VERSION 5.8 ;
BUSBITCHARS "[]" ;
DIVIDERCHAR "/" ;
UNITS
    DATABASE MICRONS 1000 ;
END UNITS

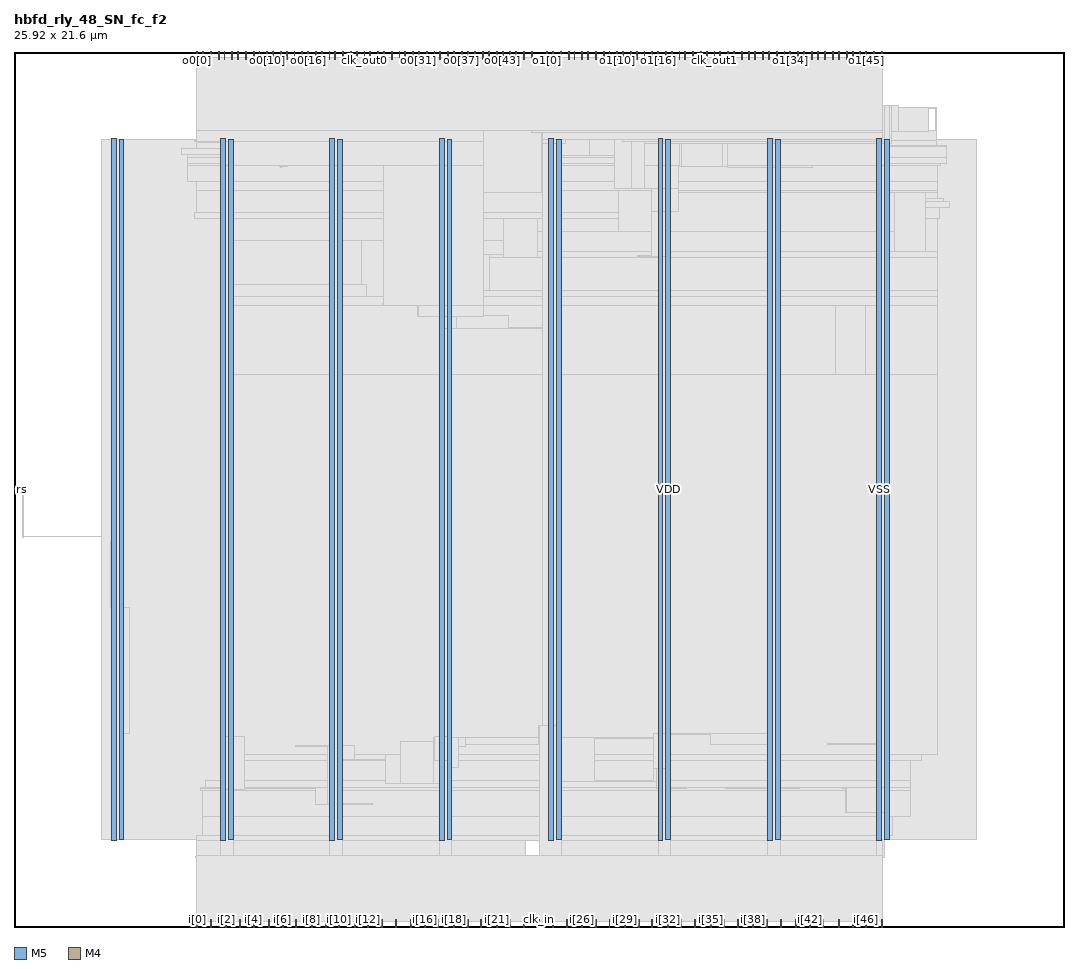
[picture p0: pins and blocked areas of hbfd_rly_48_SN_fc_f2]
MACRO hbfd_rly_48_SN_fc_f2
  FOREIGN hbfd_rly_48_SN_fc_f2 0 0 ;
  CLASS BLOCK ;
  SIZE 25.92 BY 21.6 ;
  PIN clk_in
    DIRECTION INPUT ;
    USE SIGNAL ;
    PORT
      LAYER M5 ;
        RECT  12.96 0 12.984 0.192 ;
    END
  END clk_in
  PIN clk_out0
    DIRECTION OUTPUT ;
    USE SIGNAL ;
    PORT
      LAYER M5 ;
        RECT  8.64 21.408 8.664 21.6 ;
    END
  END clk_out0
  PIN clk_out1
    DIRECTION OUTPUT ;
    USE SIGNAL ;
    PORT
      LAYER M5 ;
        RECT  17.28 21.408 17.304 21.6 ;
    END
  END clk_out1
  PIN i[0]
    DIRECTION INPUT ;
    USE SIGNAL ;
    PORT
      LAYER M5 ;
        RECT  4.512 0 4.536 0.192 ;
    END
  END i[0]
  PIN i[10]
    DIRECTION INPUT ;
    USE SIGNAL ;
    PORT
      LAYER M5 ;
        RECT  8.016 0 8.04 0.192 ;
    END
  END i[10]
  PIN i[11]
    DIRECTION INPUT ;
    USE SIGNAL ;
    PORT
      LAYER M5 ;
        RECT  8.4 0 8.424 0.192 ;
    END
  END i[11]
  PIN i[12]
    DIRECTION INPUT ;
    USE SIGNAL ;
    PORT
      LAYER M5 ;
        RECT  8.736 0 8.76 0.192 ;
    END
  END i[12]
  PIN i[13]
    DIRECTION INPUT ;
    USE SIGNAL ;
    PORT
      LAYER M5 ;
        RECT  9.072 0 9.096 0.192 ;
    END
  END i[13]
  PIN i[14]
    DIRECTION INPUT ;
    USE SIGNAL ;
    PORT
      LAYER M5 ;
        RECT  9.408 0 9.432 0.192 ;
    END
  END i[14]
  PIN i[15]
    DIRECTION INPUT ;
    USE SIGNAL ;
    PORT
      LAYER M5 ;
        RECT  9.792 0 9.816 0.192 ;
    END
  END i[15]
  PIN i[16]
    DIRECTION INPUT ;
    USE SIGNAL ;
    PORT
      LAYER M5 ;
        RECT  10.128 0 10.152 0.192 ;
    END
  END i[16]
  PIN i[17]
    DIRECTION INPUT ;
    USE SIGNAL ;
    PORT
      LAYER M5 ;
        RECT  10.464 0 10.488 0.192 ;
    END
  END i[17]
  PIN i[18]
    DIRECTION INPUT ;
    USE SIGNAL ;
    PORT
      LAYER M5 ;
        RECT  10.848 0 10.872 0.192 ;
    END
  END i[18]
  PIN i[19]
    DIRECTION INPUT ;
    USE SIGNAL ;
    PORT
      LAYER M5 ;
        RECT  11.184 0 11.208 0.192 ;
    END
  END i[19]
  PIN i[1]
    DIRECTION INPUT ;
    USE SIGNAL ;
    PORT
      LAYER M5 ;
        RECT  4.848 0 4.872 0.192 ;
    END
  END i[1]
  PIN i[20]
    DIRECTION INPUT ;
    USE SIGNAL ;
    PORT
      LAYER M5 ;
        RECT  11.52 0 11.544 0.192 ;
    END
  END i[20]
  PIN i[21]
    DIRECTION INPUT ;
    USE SIGNAL ;
    PORT
      LAYER M5 ;
        RECT  11.904 0 11.928 0.192 ;
    END
  END i[21]
  PIN i[22]
    DIRECTION INPUT ;
    USE SIGNAL ;
    PORT
      LAYER M5 ;
        RECT  12.24 0 12.264 0.192 ;
    END
  END i[22]
  PIN i[23]
    DIRECTION INPUT ;
    USE SIGNAL ;
    PORT
      LAYER M5 ;
        RECT  12.576 0 12.6 0.192 ;
    END
  END i[23]
  PIN i[24]
    DIRECTION INPUT ;
    USE SIGNAL ;
    PORT
      LAYER M5 ;
        RECT  13.296 0 13.32 0.192 ;
    END
  END i[24]
  PIN i[25]
    DIRECTION INPUT ;
    USE SIGNAL ;
    PORT
      LAYER M5 ;
        RECT  13.632 0 13.656 0.192 ;
    END
  END i[25]
  PIN i[26]
    DIRECTION INPUT ;
    USE SIGNAL ;
    PORT
      LAYER M5 ;
        RECT  14.016 0 14.04 0.192 ;
    END
  END i[26]
  PIN i[27]
    DIRECTION INPUT ;
    USE SIGNAL ;
    PORT
      LAYER M5 ;
        RECT  14.352 0 14.376 0.192 ;
    END
  END i[27]
  PIN i[28]
    DIRECTION INPUT ;
    USE SIGNAL ;
    PORT
      LAYER M5 ;
        RECT  14.688 0 14.712 0.192 ;
    END
  END i[28]
  PIN i[29]
    DIRECTION INPUT ;
    USE SIGNAL ;
    PORT
      LAYER M5 ;
        RECT  15.072 0 15.096 0.192 ;
    END
  END i[29]
  PIN i[2]
    DIRECTION INPUT ;
    USE SIGNAL ;
    PORT
      LAYER M5 ;
        RECT  5.232 0 5.256 0.192 ;
    END
  END i[2]
  PIN i[30]
    DIRECTION INPUT ;
    USE SIGNAL ;
    PORT
      LAYER M5 ;
        RECT  15.408 0 15.432 0.192 ;
    END
  END i[30]
  PIN i[31]
    DIRECTION INPUT ;
    USE SIGNAL ;
    PORT
      LAYER M5 ;
        RECT  15.744 0 15.768 0.192 ;
    END
  END i[31]
  PIN i[32]
    DIRECTION INPUT ;
    USE SIGNAL ;
    PORT
      LAYER M5 ;
        RECT  16.128 0 16.152 0.192 ;
    END
  END i[32]
  PIN i[33]
    DIRECTION INPUT ;
    USE SIGNAL ;
    PORT
      LAYER M5 ;
        RECT  16.464 0 16.488 0.192 ;
    END
  END i[33]
  PIN i[34]
    DIRECTION INPUT ;
    USE SIGNAL ;
    PORT
      LAYER M5 ;
        RECT  16.8 0 16.824 0.192 ;
    END
  END i[34]
  PIN i[35]
    DIRECTION INPUT ;
    USE SIGNAL ;
    PORT
      LAYER M5 ;
        RECT  17.184 0 17.208 0.192 ;
    END
  END i[35]
  PIN i[36]
    DIRECTION INPUT ;
    USE SIGNAL ;
    PORT
      LAYER M5 ;
        RECT  17.52 0 17.544 0.192 ;
    END
  END i[36]
  PIN i[37]
    DIRECTION INPUT ;
    USE SIGNAL ;
    PORT
      LAYER M5 ;
        RECT  17.856 0 17.88 0.192 ;
    END
  END i[37]
  PIN i[38]
    DIRECTION INPUT ;
    USE SIGNAL ;
    PORT
      LAYER M5 ;
        RECT  18.24 0 18.264 0.192 ;
    END
  END i[38]
  PIN i[39]
    DIRECTION INPUT ;
    USE SIGNAL ;
    PORT
      LAYER M5 ;
        RECT  18.576 0 18.6 0.192 ;
    END
  END i[39]
  PIN i[3]
    DIRECTION INPUT ;
    USE SIGNAL ;
    PORT
      LAYER M5 ;
        RECT  5.568 0 5.592 0.192 ;
    END
  END i[3]
  PIN i[40]
    DIRECTION INPUT ;
    USE SIGNAL ;
    PORT
      LAYER M5 ;
        RECT  18.912 0 18.936 0.192 ;
    END
  END i[40]
  PIN i[41]
    DIRECTION INPUT ;
    USE SIGNAL ;
    PORT
      LAYER M5 ;
        RECT  19.296 0 19.32 0.192 ;
    END
  END i[41]
  PIN i[42]
    DIRECTION INPUT ;
    USE SIGNAL ;
    PORT
      LAYER M5 ;
        RECT  19.632 0 19.656 0.192 ;
    END
  END i[42]
  PIN i[43]
    DIRECTION INPUT ;
    USE SIGNAL ;
    PORT
      LAYER M5 ;
        RECT  19.968 0 19.992 0.192 ;
    END
  END i[43]
  PIN i[44]
    DIRECTION INPUT ;
    USE SIGNAL ;
    PORT
      LAYER M5 ;
        RECT  20.352 0 20.376 0.192 ;
    END
  END i[44]
  PIN i[45]
    DIRECTION INPUT ;
    USE SIGNAL ;
    PORT
      LAYER M5 ;
        RECT  20.688 0 20.712 0.192 ;
    END
  END i[45]
  PIN i[46]
    DIRECTION INPUT ;
    USE SIGNAL ;
    PORT
      LAYER M5 ;
        RECT  21.024 0 21.048 0.192 ;
    END
  END i[46]
  PIN i[47]
    DIRECTION INPUT ;
    USE SIGNAL ;
    PORT
      LAYER M5 ;
        RECT  21.408 0 21.432 0.192 ;
    END
  END i[47]
  PIN i[4]
    DIRECTION INPUT ;
    USE SIGNAL ;
    PORT
      LAYER M5 ;
        RECT  5.904 0 5.928 0.192 ;
    END
  END i[4]
  PIN i[5]
    DIRECTION INPUT ;
    USE SIGNAL ;
    PORT
      LAYER M5 ;
        RECT  6.288 0 6.312 0.192 ;
    END
  END i[5]
  PIN i[6]
    DIRECTION INPUT ;
    USE SIGNAL ;
    PORT
      LAYER M5 ;
        RECT  6.624 0 6.648 0.192 ;
    END
  END i[6]
  PIN i[7]
    DIRECTION INPUT ;
    USE SIGNAL ;
    PORT
      LAYER M5 ;
        RECT  6.96 0 6.984 0.192 ;
    END
  END i[7]
  PIN i[8]
    DIRECTION INPUT ;
    USE SIGNAL ;
    PORT
      LAYER M5 ;
        RECT  7.344 0 7.368 0.192 ;
    END
  END i[8]
  PIN i[9]
    DIRECTION INPUT ;
    USE SIGNAL ;
    PORT
      LAYER M5 ;
        RECT  7.68 0 7.704 0.192 ;
    END
  END i[9]
  PIN o0[0]
    DIRECTION OUTPUT ;
    USE SIGNAL ;
    PORT
      LAYER M5 ;
        RECT  4.512 21.408 4.536 21.6 ;
    END
  END o0[0]
  PIN o0[10]
    DIRECTION OUTPUT ;
    USE SIGNAL ;
    PORT
      LAYER M5 ;
        RECT  6.24 21.408 6.264 21.6 ;
    END
  END o0[10]
  PIN o0[11]
    DIRECTION OUTPUT ;
    USE SIGNAL ;
    PORT
      LAYER M5 ;
        RECT  6.384 21.408 6.408 21.6 ;
    END
  END o0[11]
  PIN o0[12]
    DIRECTION OUTPUT ;
    USE SIGNAL ;
    PORT
      LAYER M5 ;
        RECT  6.576 21.408 6.6 21.6 ;
    END
  END o0[12]
  PIN o0[13]
    DIRECTION OUTPUT ;
    USE SIGNAL ;
    PORT
      LAYER M5 ;
        RECT  6.72 21.408 6.744 21.6 ;
    END
  END o0[13]
  PIN o0[14]
    DIRECTION OUTPUT ;
    USE SIGNAL ;
    PORT
      LAYER M5 ;
        RECT  6.912 21.408 6.936 21.6 ;
    END
  END o0[14]
  PIN o0[15]
    DIRECTION OUTPUT ;
    USE SIGNAL ;
    PORT
      LAYER M5 ;
        RECT  7.104 21.408 7.128 21.6 ;
    END
  END o0[15]
  PIN o0[16]
    DIRECTION OUTPUT ;
    USE SIGNAL ;
    PORT
      LAYER M5 ;
        RECT  7.248 21.408 7.272 21.6 ;
    END
  END o0[16]
  PIN o0[17]
    DIRECTION OUTPUT ;
    USE SIGNAL ;
    PORT
      LAYER M5 ;
        RECT  7.44 21.408 7.464 21.6 ;
    END
  END o0[17]
  PIN o0[18]
    DIRECTION OUTPUT ;
    USE SIGNAL ;
    PORT
      LAYER M5 ;
        RECT  7.584 21.408 7.608 21.6 ;
    END
  END o0[18]
  PIN o0[19]
    DIRECTION OUTPUT ;
    USE SIGNAL ;
    PORT
      LAYER M5 ;
        RECT  7.776 21.408 7.8 21.6 ;
    END
  END o0[19]
  PIN o0[1]
    DIRECTION OUTPUT ;
    USE SIGNAL ;
    PORT
      LAYER M5 ;
        RECT  4.656 21.408 4.68 21.6 ;
    END
  END o0[1]
  PIN o0[20]
    DIRECTION OUTPUT ;
    USE SIGNAL ;
    PORT
      LAYER M5 ;
        RECT  7.92 21.408 7.944 21.6 ;
    END
  END o0[20]
  PIN o0[21]
    DIRECTION OUTPUT ;
    USE SIGNAL ;
    PORT
      LAYER M5 ;
        RECT  8.112 21.408 8.136 21.6 ;
    END
  END o0[21]
  PIN o0[22]
    DIRECTION OUTPUT ;
    USE SIGNAL ;
    PORT
      LAYER M5 ;
        RECT  8.304 21.408 8.328 21.6 ;
    END
  END o0[22]
  PIN o0[23]
    DIRECTION OUTPUT ;
    USE SIGNAL ;
    PORT
      LAYER M5 ;
        RECT  8.448 21.408 8.472 21.6 ;
    END
  END o0[23]
  PIN o0[24]
    DIRECTION OUTPUT ;
    USE SIGNAL ;
    PORT
      LAYER M5 ;
        RECT  8.784 21.408 8.808 21.6 ;
    END
  END o0[24]
  PIN o0[25]
    DIRECTION OUTPUT ;
    USE SIGNAL ;
    PORT
      LAYER M5 ;
        RECT  8.976 21.408 9 21.6 ;
    END
  END o0[25]
  PIN o0[26]
    DIRECTION OUTPUT ;
    USE SIGNAL ;
    PORT
      LAYER M5 ;
        RECT  9.12 21.408 9.144 21.6 ;
    END
  END o0[26]
  PIN o0[27]
    DIRECTION OUTPUT ;
    USE SIGNAL ;
    PORT
      LAYER M5 ;
        RECT  9.312 21.408 9.336 21.6 ;
    END
  END o0[27]
  PIN o0[28]
    DIRECTION OUTPUT ;
    USE SIGNAL ;
    PORT
      LAYER M5 ;
        RECT  9.504 21.408 9.528 21.6 ;
    END
  END o0[28]
  PIN o0[29]
    DIRECTION OUTPUT ;
    USE SIGNAL ;
    PORT
      LAYER M5 ;
        RECT  9.648 21.408 9.672 21.6 ;
    END
  END o0[29]
  PIN o0[2]
    DIRECTION OUTPUT ;
    USE SIGNAL ;
    PORT
      LAYER M5 ;
        RECT  4.848 21.408 4.872 21.6 ;
    END
  END o0[2]
  PIN o0[30]
    DIRECTION OUTPUT ;
    USE SIGNAL ;
    PORT
      LAYER M5 ;
        RECT  9.84 21.408 9.864 21.6 ;
    END
  END o0[30]
  PIN o0[31]
    DIRECTION OUTPUT ;
    USE SIGNAL ;
    PORT
      LAYER M5 ;
        RECT  9.984 21.408 10.008 21.6 ;
    END
  END o0[31]
  PIN o0[32]
    DIRECTION OUTPUT ;
    USE SIGNAL ;
    PORT
      LAYER M5 ;
        RECT  10.176 21.408 10.2 21.6 ;
    END
  END o0[32]
  PIN o0[33]
    DIRECTION OUTPUT ;
    USE SIGNAL ;
    PORT
      LAYER M5 ;
        RECT  10.368 21.408 10.392 21.6 ;
    END
  END o0[33]
  PIN o0[34]
    DIRECTION OUTPUT ;
    USE SIGNAL ;
    PORT
      LAYER M5 ;
        RECT  10.512 21.408 10.536 21.6 ;
    END
  END o0[34]
  PIN o0[35]
    DIRECTION OUTPUT ;
    USE SIGNAL ;
    PORT
      LAYER M5 ;
        RECT  10.704 21.408 10.728 21.6 ;
    END
  END o0[35]
  PIN o0[36]
    DIRECTION OUTPUT ;
    USE SIGNAL ;
    PORT
      LAYER M5 ;
        RECT  10.848 21.408 10.872 21.6 ;
    END
  END o0[36]
  PIN o0[37]
    DIRECTION OUTPUT ;
    USE SIGNAL ;
    PORT
      LAYER M5 ;
        RECT  11.04 21.408 11.064 21.6 ;
    END
  END o0[37]
  PIN o0[38]
    DIRECTION OUTPUT ;
    USE SIGNAL ;
    PORT
      LAYER M5 ;
        RECT  11.184 21.408 11.208 21.6 ;
    END
  END o0[38]
  PIN o0[39]
    DIRECTION OUTPUT ;
    USE SIGNAL ;
    PORT
      LAYER M5 ;
        RECT  11.376 21.408 11.4 21.6 ;
    END
  END o0[39]
  PIN o0[3]
    DIRECTION OUTPUT ;
    USE SIGNAL ;
    PORT
      LAYER M5 ;
        RECT  5.04 21.408 5.064 21.6 ;
    END
  END o0[3]
  PIN o0[40]
    DIRECTION OUTPUT ;
    USE SIGNAL ;
    PORT
      LAYER M5 ;
        RECT  11.568 21.408 11.592 21.6 ;
    END
  END o0[40]
  PIN o0[41]
    DIRECTION OUTPUT ;
    USE SIGNAL ;
    PORT
      LAYER M5 ;
        RECT  11.712 21.408 11.736 21.6 ;
    END
  END o0[41]
  PIN o0[42]
    DIRECTION OUTPUT ;
    USE SIGNAL ;
    PORT
      LAYER M5 ;
        RECT  11.904 21.408 11.928 21.6 ;
    END
  END o0[42]
  PIN o0[43]
    DIRECTION OUTPUT ;
    USE SIGNAL ;
    PORT
      LAYER M5 ;
        RECT  12.048 21.408 12.072 21.6 ;
    END
  END o0[43]
  PIN o0[44]
    DIRECTION OUTPUT ;
    USE SIGNAL ;
    PORT
      LAYER M5 ;
        RECT  12.24 21.408 12.264 21.6 ;
    END
  END o0[44]
  PIN o0[45]
    DIRECTION OUTPUT ;
    USE SIGNAL ;
    PORT
      LAYER M5 ;
        RECT  12.384 21.408 12.408 21.6 ;
    END
  END o0[45]
  PIN o0[46]
    DIRECTION OUTPUT ;
    USE SIGNAL ;
    PORT
      LAYER M5 ;
        RECT  12.576 21.408 12.6 21.6 ;
    END
  END o0[46]
  PIN o0[47]
    DIRECTION OUTPUT ;
    USE SIGNAL ;
    PORT
      LAYER M5 ;
        RECT  12.768 21.408 12.792 21.6 ;
    END
  END o0[47]
  PIN o0[4]
    DIRECTION OUTPUT ;
    USE SIGNAL ;
    PORT
      LAYER M5 ;
        RECT  5.184 21.408 5.208 21.6 ;
    END
  END o0[4]
  PIN o0[5]
    DIRECTION OUTPUT ;
    USE SIGNAL ;
    PORT
      LAYER M5 ;
        RECT  5.376 21.408 5.4 21.6 ;
    END
  END o0[5]
  PIN o0[6]
    DIRECTION OUTPUT ;
    USE SIGNAL ;
    PORT
      LAYER M5 ;
        RECT  5.52 21.408 5.544 21.6 ;
    END
  END o0[6]
  PIN o0[7]
    DIRECTION OUTPUT ;
    USE SIGNAL ;
    PORT
      LAYER M5 ;
        RECT  5.712 21.408 5.736 21.6 ;
    END
  END o0[7]
  PIN o0[8]
    DIRECTION OUTPUT ;
    USE SIGNAL ;
    PORT
      LAYER M5 ;
        RECT  5.904 21.408 5.928 21.6 ;
    END
  END o0[8]
  PIN o0[9]
    DIRECTION OUTPUT ;
    USE SIGNAL ;
    PORT
      LAYER M5 ;
        RECT  6.048 21.408 6.072 21.6 ;
    END
  END o0[9]
  PIN o1[0]
    DIRECTION OUTPUT ;
    USE SIGNAL ;
    PORT
      LAYER M5 ;
        RECT  13.152 21.408 13.176 21.6 ;
    END
  END o1[0]
  PIN o1[10]
    DIRECTION OUTPUT ;
    USE SIGNAL ;
    PORT
      LAYER M5 ;
        RECT  14.88 21.408 14.904 21.6 ;
    END
  END o1[10]
  PIN o1[11]
    DIRECTION OUTPUT ;
    USE SIGNAL ;
    PORT
      LAYER M5 ;
        RECT  15.024 21.408 15.048 21.6 ;
    END
  END o1[11]
  PIN o1[12]
    DIRECTION OUTPUT ;
    USE SIGNAL ;
    PORT
      LAYER M5 ;
        RECT  15.216 21.408 15.24 21.6 ;
    END
  END o1[12]
  PIN o1[13]
    DIRECTION OUTPUT ;
    USE SIGNAL ;
    PORT
      LAYER M5 ;
        RECT  15.36 21.408 15.384 21.6 ;
    END
  END o1[13]
  PIN o1[14]
    DIRECTION OUTPUT ;
    USE SIGNAL ;
    PORT
      LAYER M5 ;
        RECT  15.552 21.408 15.576 21.6 ;
    END
  END o1[14]
  PIN o1[15]
    DIRECTION OUTPUT ;
    USE SIGNAL ;
    PORT
      LAYER M5 ;
        RECT  15.744 21.408 15.768 21.6 ;
    END
  END o1[15]
  PIN o1[16]
    DIRECTION OUTPUT ;
    USE SIGNAL ;
    PORT
      LAYER M5 ;
        RECT  15.888 21.408 15.912 21.6 ;
    END
  END o1[16]
  PIN o1[17]
    DIRECTION OUTPUT ;
    USE SIGNAL ;
    PORT
      LAYER M5 ;
        RECT  16.08 21.408 16.104 21.6 ;
    END
  END o1[17]
  PIN o1[18]
    DIRECTION OUTPUT ;
    USE SIGNAL ;
    PORT
      LAYER M5 ;
        RECT  16.224 21.408 16.248 21.6 ;
    END
  END o1[18]
  PIN o1[19]
    DIRECTION OUTPUT ;
    USE SIGNAL ;
    PORT
      LAYER M5 ;
        RECT  16.416 21.408 16.44 21.6 ;
    END
  END o1[19]
  PIN o1[1]
    DIRECTION OUTPUT ;
    USE SIGNAL ;
    PORT
      LAYER M5 ;
        RECT  13.296 21.408 13.32 21.6 ;
    END
  END o1[1]
  PIN o1[20]
    DIRECTION OUTPUT ;
    USE SIGNAL ;
    PORT
      LAYER M5 ;
        RECT  16.56 21.408 16.584 21.6 ;
    END
  END o1[20]
  PIN o1[21]
    DIRECTION OUTPUT ;
    USE SIGNAL ;
    PORT
      LAYER M5 ;
        RECT  16.752 21.408 16.776 21.6 ;
    END
  END o1[21]
  PIN o1[22]
    DIRECTION OUTPUT ;
    USE SIGNAL ;
    PORT
      LAYER M5 ;
        RECT  16.944 21.408 16.968 21.6 ;
    END
  END o1[22]
  PIN o1[23]
    DIRECTION OUTPUT ;
    USE SIGNAL ;
    PORT
      LAYER M5 ;
        RECT  17.088 21.408 17.112 21.6 ;
    END
  END o1[23]
  PIN o1[24]
    DIRECTION OUTPUT ;
    USE SIGNAL ;
    PORT
      LAYER M5 ;
        RECT  17.424 21.408 17.448 21.6 ;
    END
  END o1[24]
  PIN o1[25]
    DIRECTION OUTPUT ;
    USE SIGNAL ;
    PORT
      LAYER M5 ;
        RECT  17.616 21.408 17.64 21.6 ;
    END
  END o1[25]
  PIN o1[26]
    DIRECTION OUTPUT ;
    USE SIGNAL ;
    PORT
      LAYER M5 ;
        RECT  17.76 21.408 17.784 21.6 ;
    END
  END o1[26]
  PIN o1[27]
    DIRECTION OUTPUT ;
    USE SIGNAL ;
    PORT
      LAYER M5 ;
        RECT  17.952 21.408 17.976 21.6 ;
    END
  END o1[27]
  PIN o1[28]
    DIRECTION OUTPUT ;
    USE SIGNAL ;
    PORT
      LAYER M5 ;
        RECT  18.144 21.408 18.168 21.6 ;
    END
  END o1[28]
  PIN o1[29]
    DIRECTION OUTPUT ;
    USE SIGNAL ;
    PORT
      LAYER M5 ;
        RECT  18.288 21.408 18.312 21.6 ;
    END
  END o1[29]
  PIN o1[2]
    DIRECTION OUTPUT ;
    USE SIGNAL ;
    PORT
      LAYER M5 ;
        RECT  13.488 21.408 13.512 21.6 ;
    END
  END o1[2]
  PIN o1[30]
    DIRECTION OUTPUT ;
    USE SIGNAL ;
    PORT
      LAYER M5 ;
        RECT  18.48 21.408 18.504 21.6 ;
    END
  END o1[30]
  PIN o1[31]
    DIRECTION OUTPUT ;
    USE SIGNAL ;
    PORT
      LAYER M5 ;
        RECT  18.624 21.408 18.648 21.6 ;
    END
  END o1[31]
  PIN o1[32]
    DIRECTION OUTPUT ;
    USE SIGNAL ;
    PORT
      LAYER M5 ;
        RECT  18.816 21.408 18.84 21.6 ;
    END
  END o1[32]
  PIN o1[33]
    DIRECTION OUTPUT ;
    USE SIGNAL ;
    PORT
      LAYER M5 ;
        RECT  19.008 21.408 19.032 21.6 ;
    END
  END o1[33]
  PIN o1[34]
    DIRECTION OUTPUT ;
    USE SIGNAL ;
    PORT
      LAYER M5 ;
        RECT  19.152 21.408 19.176 21.6 ;
    END
  END o1[34]
  PIN o1[35]
    DIRECTION OUTPUT ;
    USE SIGNAL ;
    PORT
      LAYER M5 ;
        RECT  19.344 21.408 19.368 21.6 ;
    END
  END o1[35]
  PIN o1[36]
    DIRECTION OUTPUT ;
    USE SIGNAL ;
    PORT
      LAYER M5 ;
        RECT  19.488 21.408 19.512 21.6 ;
    END
  END o1[36]
  PIN o1[37]
    DIRECTION OUTPUT ;
    USE SIGNAL ;
    PORT
      LAYER M5 ;
        RECT  19.68 21.408 19.704 21.6 ;
    END
  END o1[37]
  PIN o1[38]
    DIRECTION OUTPUT ;
    USE SIGNAL ;
    PORT
      LAYER M5 ;
        RECT  19.824 21.408 19.848 21.6 ;
    END
  END o1[38]
  PIN o1[39]
    DIRECTION OUTPUT ;
    USE SIGNAL ;
    PORT
      LAYER M5 ;
        RECT  20.016 21.408 20.04 21.6 ;
    END
  END o1[39]
  PIN o1[3]
    DIRECTION OUTPUT ;
    USE SIGNAL ;
    PORT
      LAYER M5 ;
        RECT  13.68 21.408 13.704 21.6 ;
    END
  END o1[3]
  PIN o1[40]
    DIRECTION OUTPUT ;
    USE SIGNAL ;
    PORT
      LAYER M5 ;
        RECT  20.208 21.408 20.232 21.6 ;
    END
  END o1[40]
  PIN o1[41]
    DIRECTION OUTPUT ;
    USE SIGNAL ;
    PORT
      LAYER M5 ;
        RECT  20.352 21.408 20.376 21.6 ;
    END
  END o1[41]
  PIN o1[42]
    DIRECTION OUTPUT ;
    USE SIGNAL ;
    PORT
      LAYER M5 ;
        RECT  20.544 21.408 20.568 21.6 ;
    END
  END o1[42]
  PIN o1[43]
    DIRECTION OUTPUT ;
    USE SIGNAL ;
    PORT
      LAYER M5 ;
        RECT  20.688 21.408 20.712 21.6 ;
    END
  END o1[43]
  PIN o1[44]
    DIRECTION OUTPUT ;
    USE SIGNAL ;
    PORT
      LAYER M5 ;
        RECT  20.88 21.408 20.904 21.6 ;
    END
  END o1[44]
  PIN o1[45]
    DIRECTION OUTPUT ;
    USE SIGNAL ;
    PORT
      LAYER M5 ;
        RECT  21.024 21.408 21.048 21.6 ;
    END
  END o1[45]
  PIN o1[46]
    DIRECTION OUTPUT ;
    USE SIGNAL ;
    PORT
      LAYER M5 ;
        RECT  21.216 21.408 21.24 21.6 ;
    END
  END o1[46]
  PIN o1[47]
    DIRECTION OUTPUT ;
    USE SIGNAL ;
    PORT
      LAYER M5 ;
        RECT  21.408 21.408 21.432 21.6 ;
    END
  END o1[47]
  PIN o1[4]
    DIRECTION OUTPUT ;
    USE SIGNAL ;
    PORT
      LAYER M5 ;
        RECT  13.824 21.408 13.848 21.6 ;
    END
  END o1[4]
  PIN o1[5]
    DIRECTION OUTPUT ;
    USE SIGNAL ;
    PORT
      LAYER M5 ;
        RECT  14.016 21.408 14.04 21.6 ;
    END
  END o1[5]
  PIN o1[6]
    DIRECTION OUTPUT ;
    USE SIGNAL ;
    PORT
      LAYER M5 ;
        RECT  14.16 21.408 14.184 21.6 ;
    END
  END o1[6]
  PIN o1[7]
    DIRECTION OUTPUT ;
    USE SIGNAL ;
    PORT
      LAYER M5 ;
        RECT  14.352 21.408 14.376 21.6 ;
    END
  END o1[7]
  PIN o1[8]
    DIRECTION OUTPUT ;
    USE SIGNAL ;
    PORT
      LAYER M5 ;
        RECT  14.544 21.408 14.568 21.6 ;
    END
  END o1[8]
  PIN o1[9]
    DIRECTION OUTPUT ;
    USE SIGNAL ;
    PORT
      LAYER M5 ;
        RECT  14.688 21.408 14.712 21.6 ;
    END
  END o1[9]
  PIN rs
    DIRECTION INPUT ;
    USE SIGNAL ;
    PORT
      LAYER M4 ;
        RECT  0 10.8 0.192 10.824 ;
    END
  END rs
  PIN VDD
    DIRECTION INOUT ;
    USE POWER ;
    PORT
      LAYER M5 ;
        RECT  21.492 2.151 21.612 19.449 ;
        RECT  18.792 2.151 18.912 19.449 ;
        RECT  16.092 2.151 16.212 19.449 ;
        RECT  13.392 2.151 13.512 19.449 ;
        RECT  10.692 2.151 10.812 19.449 ;
        RECT  7.992 2.151 8.112 19.449 ;
        RECT  5.292 2.151 5.412 19.449 ;
        RECT  2.592 2.151 2.712 19.449 ;
    END
  END VDD
  PIN VSS
    DIRECTION INOUT ;
    USE GROUND ;
    PORT
      LAYER M5 ;
        RECT  21.3 2.137 21.42 19.463 ;
        RECT  18.6 2.137 18.72 19.463 ;
        RECT  15.9 2.137 16.02 19.463 ;
        RECT  13.2 2.137 13.32 19.463 ;
        RECT  10.5 2.137 10.62 19.463 ;
        RECT  7.8 2.137 7.92 19.463 ;
        RECT  5.1 2.137 5.22 19.463 ;
        RECT  2.4 2.137 2.52 19.463 ;
    END
  END VSS
  OBS
    LAYER RVTN ;
     RECT  2.16 2.16 23.76 2.295 ;
     RECT  2.16 2.565 23.76 2.835 ;
     RECT  2.16 3.105 23.76 3.375 ;
     RECT  2.16 3.645 23.76 3.915 ;
     RECT  2.16 4.185 23.76 4.455 ;
     RECT  2.16 4.725 23.76 4.995 ;
     RECT  2.16 5.265 23.76 5.535 ;
     RECT  2.16 5.805 23.76 6.075 ;
     RECT  2.16 6.345 23.76 6.615 ;
     RECT  2.16 6.885 23.76 7.155 ;
     RECT  2.16 7.425 23.76 7.695 ;
     RECT  2.16 7.965 23.76 8.235 ;
     RECT  2.16 8.505 23.76 8.775 ;
     RECT  2.16 9.045 23.76 9.315 ;
     RECT  2.16 9.585 23.76 9.855 ;
     RECT  2.16 10.125 23.76 10.395 ;
     RECT  2.16 10.665 23.76 10.935 ;
     RECT  2.16 11.205 23.76 11.475 ;
     RECT  2.16 11.745 23.76 12.015 ;
     RECT  2.16 12.285 23.76 12.555 ;
     RECT  2.16 12.825 23.76 13.095 ;
     RECT  2.16 13.365 23.76 13.635 ;
     RECT  2.16 13.905 23.76 14.175 ;
     RECT  2.16 14.445 23.76 14.715 ;
     RECT  2.16 14.985 23.76 15.255 ;
     RECT  2.16 15.525 23.76 15.795 ;
     RECT  2.16 16.065 23.76 16.335 ;
     RECT  2.16 16.605 23.76 16.875 ;
     RECT  2.16 17.145 23.76 17.415 ;
     RECT  2.16 17.685 23.76 17.955 ;
     RECT  2.16 18.225 23.76 18.495 ;
     RECT  2.16 18.765 23.76 19.035 ;
     RECT  2.16 19.305 23.76 19.44 ;
    LAYER RVTP ;
     RECT  2.16 2.295 23.76 2.565 ;
     RECT  2.16 2.835 23.76 3.105 ;
     RECT  2.16 3.375 23.76 3.645 ;
     RECT  2.16 3.915 23.76 4.185 ;
     RECT  2.16 4.455 23.76 4.725 ;
     RECT  2.16 4.995 23.76 5.265 ;
     RECT  2.16 5.535 23.76 5.805 ;
     RECT  2.16 6.075 23.76 6.345 ;
     RECT  2.16 6.615 23.76 6.885 ;
     RECT  2.16 7.155 23.76 7.425 ;
     RECT  2.16 7.695 23.76 7.965 ;
     RECT  2.16 8.235 23.76 8.505 ;
     RECT  2.16 8.775 23.76 9.045 ;
     RECT  2.16 9.315 23.76 9.585 ;
     RECT  2.16 9.855 23.76 10.125 ;
     RECT  2.16 10.395 23.76 10.665 ;
     RECT  2.16 10.935 23.76 11.205 ;
     RECT  2.16 11.475 23.76 11.745 ;
     RECT  2.16 12.015 23.76 12.285 ;
     RECT  2.16 12.555 23.76 12.825 ;
     RECT  2.16 13.095 23.76 13.365 ;
     RECT  2.16 13.635 23.76 13.905 ;
     RECT  2.16 14.175 23.76 14.445 ;
     RECT  2.16 14.715 23.76 14.985 ;
     RECT  2.16 15.255 23.76 15.525 ;
     RECT  2.16 15.795 23.76 16.065 ;
     RECT  2.16 16.335 23.76 16.605 ;
     RECT  2.16 16.875 23.76 17.145 ;
     RECT  2.16 17.415 23.76 17.685 ;
     RECT  2.16 17.955 23.76 18.225 ;
     RECT  2.16 18.495 23.76 18.765 ;
     RECT  2.16 19.035 23.76 19.305 ;
    LAYER M1 ;
     RECT  2.16 2.151 23.76 19.449 ;
    LAYER M2 ;
     RECT  0.211 9.63 2.16 9.648 ;
     RECT  2.16 2.151 23.76 19.449 ;
    LAYER M3 ;
     RECT  4.5 1.723 12.618 2.143 ;
     RECT  13.356 1.723 21.474 2.143 ;
     RECT  4.5 2.143 21.474 2.255 ;
     RECT  4.644 2.255 21.474 2.263 ;
     RECT  2.415 2.143 2.505 2.413 ;
     RECT  4.644 2.263 21.69 2.731 ;
     RECT  4.644 2.731 22.122 3.379 ;
     RECT  4.608 3.379 22.122 3.437 ;
     RECT  4.716 3.437 22.122 3.605 ;
     RECT  5.115 3.605 22.122 4.117 ;
     RECT  5.115 4.117 22.41 4.261 ;
     RECT  2.415 2.413 2.697 4.765 ;
     RECT  2.415 4.765 2.862 7.889 ;
     RECT  2.415 7.889 2.697 7.897 ;
     RECT  2.376 7.897 2.697 9.509 ;
     RECT  0.216 9.625 0.234 10.829 ;
     RECT  5.115 4.261 22.806 13.631 ;
     RECT  5.115 13.631 20.286 15.331 ;
     RECT  21.024 13.631 22.806 15.331 ;
     RECT  5.115 15.331 22.806 15.557 ;
     RECT  9.468 15.557 22.806 15.719 ;
     RECT  5.115 15.557 8.694 15.863 ;
     RECT  9.576 15.719 10.854 16.501 ;
     RECT  11.736 15.719 22.806 16.529 ;
     RECT  9.396 16.501 10.854 16.609 ;
     RECT  11.736 16.529 12.078 16.609 ;
     RECT  12.924 16.529 22.806 16.673 ;
     RECT  5.115 15.863 8.586 16.951 ;
     RECT  9.396 16.609 12.078 16.951 ;
     RECT  12.924 16.673 21.726 17.177 ;
     RECT  5.115 16.951 12.078 17.491 ;
     RECT  12.924 17.177 14.922 17.491 ;
     RECT  22.5 16.673 22.806 17.491 ;
     RECT  4.464 17.491 14.922 17.645 ;
     RECT  22.5 17.491 22.842 17.761 ;
     RECT  22.5 17.761 23.094 17.915 ;
     RECT  22.5 17.915 22.95 17.987 ;
     RECT  15.876 17.177 21.726 18.121 ;
     RECT  22.5 17.987 22.806 18.121 ;
     RECT  4.5 17.645 14.922 18.193 ;
     RECT  15.876 18.121 22.806 18.193 ;
     RECT  4.5 18.193 22.806 18.391 ;
     RECT  4.284 18.391 22.806 18.805 ;
     RECT  4.284 18.805 22.878 18.841 ;
     RECT  4.284 18.841 23.022 18.995 ;
     RECT  4.284 18.995 8.658 19.075 ;
     RECT  2.415 9.509 2.697 19.187 ;
     RECT  4.14 19.075 8.658 19.229 ;
     RECT  9.54 18.995 23.022 19.265 ;
     RECT  9.54 19.265 14.85 19.277 ;
     RECT  15.66 19.265 23.022 19.301 ;
     RECT  4.5 19.229 8.658 19.373 ;
     RECT  9.576 19.277 14.85 19.373 ;
     RECT  4.5 19.373 6.102 19.421 ;
     RECT  15.66 19.301 22.77 19.421 ;
     RECT  2.415 19.187 2.505 19.457 ;
     RECT  9.9 19.373 14.85 19.469 ;
     RECT  7.164 19.373 8.55 19.613 ;
     RECT  9.9 19.469 14.67 19.613 ;
     RECT  19.98 19.421 22.77 19.661 ;
     RECT  19.98 19.661 21.834 19.709 ;
     RECT  11.88 19.613 14.67 19.757 ;
     RECT  4.608 19.421 6.102 19.997 ;
     RECT  7.164 19.613 7.758 19.997 ;
     RECT  8.532 19.613 8.55 19.997 ;
     RECT  9.9 19.613 11.142 19.997 ;
     RECT  11.88 19.757 11.898 19.997 ;
     RECT  15.66 19.421 19.026 19.997 ;
     RECT  20.016 19.709 21.834 19.997 ;
     RECT  11.088 19.997 11.142 20.045 ;
     RECT  13.032 19.757 14.67 20.045 ;
     RECT  16.056 19.997 18.99 20.093 ;
     RECT  22.752 19.661 22.77 20.237 ;
     RECT  21.816 19.997 21.834 20.285 ;
     RECT  20.232 19.997 20.646 20.381 ;
     RECT  4.788 19.997 5.706 20.573 ;
     RECT  7.2 19.997 7.758 20.573 ;
     RECT  9.9 19.997 9.918 20.573 ;
     RECT  11.124 20.045 11.142 20.573 ;
     RECT  14.652 20.045 14.67 20.573 ;
     RECT  16.056 20.093 18.774 20.573 ;
     RECT  20.628 20.381 20.646 20.573 ;
     RECT  16.488 20.573 18.054 20.621 ;
     RECT  13.032 20.045 13.554 20.669 ;
     RECT  17.496 20.621 17.766 20.669 ;
     RECT  13.536 20.669 13.554 20.717 ;
     RECT  17.748 20.669 17.766 20.717 ;
    LAYER M4 ;
     RECT  0.156 10.8 0.245 10.824 ;
     RECT  2.408 2.148 2.512 19.452 ;
     RECT  2.512 2.418 2.704 19.182 ;
     RECT  4.46 19.392 4.597 19.416 ;
     RECT  4.597 19.392 4.777 19.992 ;
     RECT  4.489 1.728 5.108 1.752 ;
     RECT  4.597 3.408 5.108 3.432 ;
     RECT  4.777 19.392 5.108 20.568 ;
     RECT  5.108 1.728 5.404 20.568 ;
     RECT  5.404 4.656 5.699 4.68 ;
     RECT  5.404 19.968 5.717 20.568 ;
     RECT  5.717 19.968 6.124 19.992 ;
     RECT  5.404 18.816 6.565 18.84 ;
     RECT  6.565 18.768 6.709 18.84 ;
     RECT  6.709 18.768 6.761 19.368 ;
     RECT  6.761 18.816 7.093 19.368 ;
     RECT  6.901 20.544 7.093 20.568 ;
     RECT  5.404 3.408 7.441 3.432 ;
     RECT  7.441 3.024 7.729 3.432 ;
     RECT  6.937 4.464 7.729 4.488 ;
     RECT  7.093 18.816 7.769 20.568 ;
     RECT  5.404 1.728 7.808 1.752 ;
     RECT  7.729 3.024 7.808 4.488 ;
     RECT  7.769 18.816 7.808 19.992 ;
     RECT  7.808 1.728 8.104 19.992 ;
     RECT  8.104 4.128 8.417 4.488 ;
     RECT  8.104 18.816 8.561 19.992 ;
     RECT  8.561 18.816 8.713 19.368 ;
     RECT  8.104 3.024 8.849 3.048 ;
     RECT  8.417 4.128 9.169 4.248 ;
     RECT  9.169 3.552 9.529 4.248 ;
     RECT  9.829 20.544 9.929 20.568 ;
     RECT  9.109 15.36 9.973 15.384 ;
     RECT  8.713 18.816 10.141 19.32 ;
     RECT  10.141 18.672 10.165 19.32 ;
     RECT  9.529 3.552 10.357 4.584 ;
     RECT  10.165 18.672 10.429 19.416 ;
     RECT  8.104 1.728 10.508 1.752 ;
     RECT  10.357 3.552 10.508 4.68 ;
     RECT  9.973 15.072 10.508 15.384 ;
     RECT  10.429 18.672 10.508 19.992 ;
     RECT  10.508 1.728 10.804 19.992 ;
     RECT  10.804 3.936 10.973 4.68 ;
     RECT  10.804 18.144 11.077 19.992 ;
     RECT  11.077 18.144 11.113 20.04 ;
     RECT  10.973 4.464 11.153 4.68 ;
     RECT  10.804 14.784 12.197 15.096 ;
     RECT  11.153 4.512 12.949 4.68 ;
     RECT  11.113 18.144 13.021 20.568 ;
     RECT  10.804 1.728 13.208 1.752 ;
     RECT  12.949 4.512 13.208 4.968 ;
     RECT  12.197 14.784 13.208 14.808 ;
     RECT  13.021 18.144 13.208 20.664 ;
     RECT  13.208 1.728 13.504 20.664 ;
     RECT  13.504 19.056 13.525 20.664 ;
     RECT  13.525 19.056 14.195 20.712 ;
     RECT  13.504 3.6 14.321 4.68 ;
     RECT  14.195 19.056 14.821 20.616 ;
     RECT  14.821 18.24 15.251 20.616 ;
     RECT  14.321 3.6 15.781 3.624 ;
     RECT  14.321 4.656 15.781 4.68 ;
     RECT  15.781 3.6 15.865 4.776 ;
     RECT  13.504 1.728 15.908 1.752 ;
     RECT  15.865 3.408 15.908 4.776 ;
     RECT  15.397 16.56 15.908 16.584 ;
     RECT  15.251 18.24 15.908 20.568 ;
     RECT  15.908 1.728 16.204 20.568 ;
     RECT  16.204 17.664 16.355 20.568 ;
     RECT  16.355 17.664 16.403 17.688 ;
     RECT  16.355 18.768 16.477 20.568 ;
     RECT  16.204 3.408 16.589 3.432 ;
     RECT  16.204 4.752 17.197 4.776 ;
     RECT  16.477 18.768 17.485 20.616 ;
     RECT  17.485 18.768 17.737 20.664 ;
     RECT  17.737 18.768 18.323 20.712 ;
     RECT  18.323 18.768 18.515 20.616 ;
     RECT  16.204 1.728 18.608 1.752 ;
     RECT  17.557 3.408 18.608 3.432 ;
     RECT  17.197 4.512 18.608 4.776 ;
     RECT  18.515 18.768 18.608 20.568 ;
     RECT  18.608 1.728 18.851 20.568 ;
     RECT  18.851 1.728 18.904 20.376 ;
     RECT  18.904 3.408 19.397 3.432 ;
     RECT  18.904 18.768 19.721 20.376 ;
     RECT  20.437 3.408 20.533 3.432 ;
     RECT  19.721 18.816 20.533 20.376 ;
     RECT  20.533 18.816 20.657 20.568 ;
     RECT  18.904 1.728 21.308 1.752 ;
     RECT  20.533 2.832 21.308 3.432 ;
     RECT  20.077 4.512 21.308 4.536 ;
     RECT  20.657 18.816 21.308 20.28 ;
     RECT  21.308 1.728 21.485 20.28 ;
     RECT  21.485 2.418 21.604 20.28 ;
     RECT  21.604 19.344 21.665 20.28 ;
     RECT  21.665 19.632 21.845 20.28 ;
     RECT  21.845 19.632 22.565 20.232 ;
     RECT  22.565 20.208 22.781 20.232 ;
    LAYER M5 ;
     RECT  4.512 0.144 21.432 1.763 ;
     RECT  2.4 2.137 2.52 2.151 ;
     RECT  21.3 1.763 21.432 2.151 ;
     RECT  21.3 2.151 21.612 2.821 ;
     RECT  5.1 1.763 5.412 3.397 ;
     RECT  20.544 2.821 21.612 3.443 ;
     RECT  15.9 1.763 16.212 3.925 ;
     RECT  10.5 1.763 10.812 4.117 ;
     RECT  5.1 3.397 5.688 4.691 ;
     RECT  10.368 4.117 10.812 4.691 ;
     RECT  15.792 3.925 16.212 4.787 ;
     RECT  12.96 1.763 13.512 4.979 ;
     RECT  10.5 4.691 10.812 14.773 ;
     RECT  10.5 14.773 10.92 15.061 ;
     RECT  9.984 15.061 11.592 15.349 ;
     RECT  15.9 4.787 16.212 16.549 ;
     RECT  15.744 16.549 16.212 17.653 ;
     RECT  15.744 17.653 16.392 18.229 ;
     RECT  18.6 1.763 18.912 18.757 ;
     RECT  5.1 4.691 5.412 18.805 ;
     RECT  6.576 18.757 6.6 18.805 ;
     RECT  7.8 1.763 8.112 18.805 ;
     RECT  9.12 15.349 11.592 18.805 ;
     RECT  15.552 18.229 16.392 18.805 ;
     RECT  17.616 18.757 19.704 18.805 ;
     RECT  21.3 3.443 21.612 18.805 ;
     RECT  13.056 4.979 13.512 19.333 ;
     RECT  15.552 18.805 16.44 19.333 ;
     RECT  17.616 18.805 21.612 19.333 ;
     RECT  5.1 18.805 11.592 19.381 ;
     RECT  15.552 19.333 21.612 19.381 ;
     RECT  13.056 19.333 13.608 19.429 ;
     RECT  15.024 19.381 21.612 19.429 ;
     RECT  2.4 2.151 2.712 19.449 ;
     RECT  13.056 19.429 21.612 19.449 ;
     RECT  2.4 19.449 2.52 19.463 ;
     RECT  13.056 19.449 21.432 19.621 ;
     RECT  4.512 19.381 11.592 19.669 ;
     RECT  12.768 19.621 21.432 19.669 ;
     RECT  4.512 19.669 21.432 21.456 ;
  END
END hbfd_rly_48_SN_fc_f2
END LIBRARY
